# binner_art: generated by tools/make_art.py -- do not edit
VERSION 5.8 ;
NAMESCASESENSITIVE ON ;
DIVIDERCHAR "/" ;
BUSBITCHARS "[]" ;
UNITS
   DATABASE MICRONS 1000 ;
END UNITS

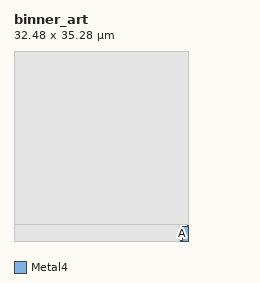
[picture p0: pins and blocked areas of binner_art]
MACRO binner_art
   CLASS BLOCK ;
   FOREIGN binner_art 0 0 ;
   ORIGIN 0 0 ;
   SIZE 32.480 BY 35.280 ;
   SYMMETRY X Y ;
   PIN A
      DIRECTION INPUT ;
      USE SIGNAL ;
      ANTENNAPARTIALMETALAREA 618.524 LAYER Metal4 ;
      ANTENNAPARTIALMETALSIDEAREA 152.150 LAYER Metal4 ;
      PORT
         LAYER Metal4 ;
            RECT 31.240 0.000 32.480 2.640 ;
      END
   END A
   OBS
      LAYER Metal4 ;
         RECT 0.000 3.140 32.480 35.280 ;
         RECT 0.000 0.000 30.740 3.140 ;
      LAYER Metal3 ;
         RECT 0.000 3.140 32.480 35.280 ;
         RECT 0.000 0.000 30.740 3.140 ;
   END
END binner_art
